VERSION 5.7 ;
  NOWIREEXTENSIONATPIN ON ;
  DIVIDERCHAR "/" ;
  BUSBITCHARS "[]" ;
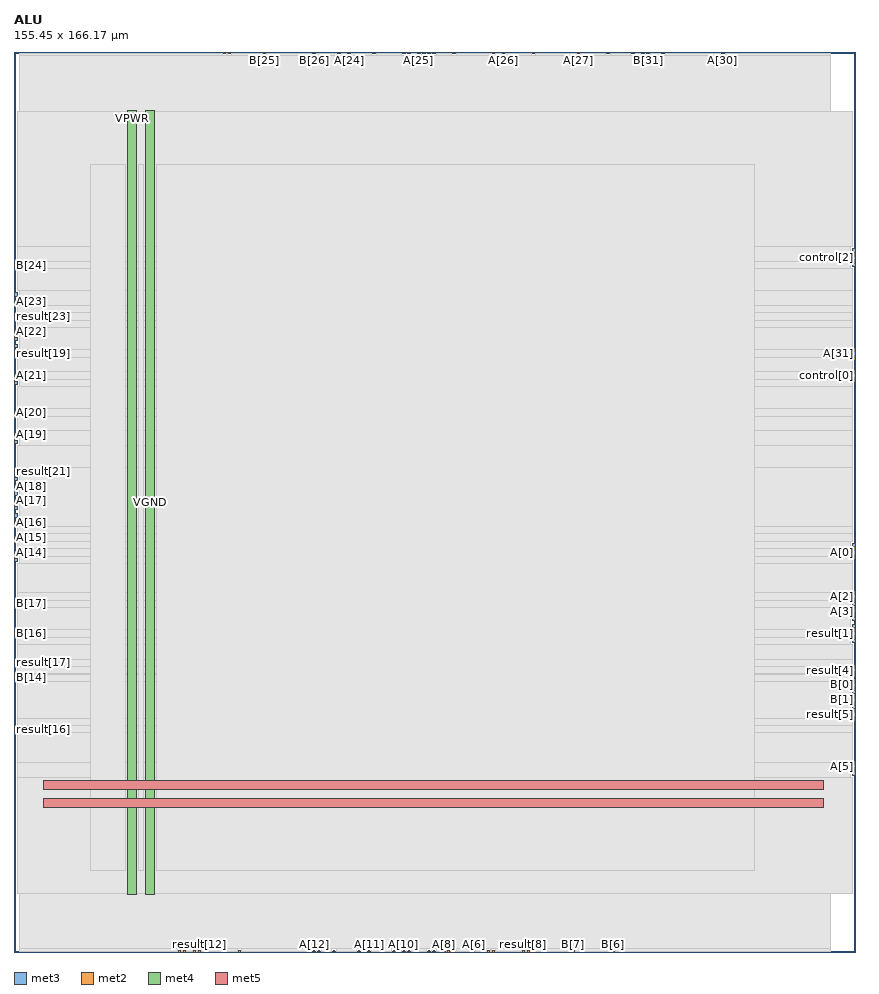
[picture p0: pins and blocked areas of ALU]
MACRO ALU
  CLASS BLOCK ;
  FOREIGN ALU ;
  ORIGIN 0.000 0.000 ;
  SIZE 155.450 BY 166.170 ;
  PIN A[0]
    DIRECTION INPUT ;
    USE SIGNAL ;
    ANTENNAGATEAREA 0.126000 ;
    PORT
      LAYER met3 ;
        RECT 154.850 73.480 155.450 74.080 ;
    END
  END A[0]
  PIN A[10]
    DIRECTION INPUT ;
    USE SIGNAL ;
    ANTENNAGATEAREA 0.213000 ;
    PORT
      LAYER met2 ;
        RECT 71.850 0.000 72.130 0.280 ;
    END
  END A[10]
  PIN A[11]
    DIRECTION INPUT ;
    USE SIGNAL ;
    ANTENNAGATEAREA 0.213000 ;
    PORT
      LAYER met2 ;
        RECT 65.410 0.000 65.690 0.280 ;
    END
  END A[11]
  PIN A[12]
    DIRECTION INPUT ;
    USE SIGNAL ;
    ANTENNAGATEAREA 0.126000 ;
    PORT
      LAYER met2 ;
        RECT 55.290 0.000 55.570 0.280 ;
    END
  END A[12]
  PIN A[13]
    DIRECTION INPUT ;
    USE SIGNAL ;
    ANTENNAGATEAREA 0.213000 ;
    PORT
      LAYER met2 ;
        RECT 30.450 0.000 30.730 0.280 ;
    END
  END A[13]
  PIN A[14]
    DIRECTION INPUT ;
    USE SIGNAL ;
    ANTENNAGATEAREA 0.126000 ;
    PORT
      LAYER met3 ;
        RECT 0.000 73.480 0.600 74.080 ;
    END
  END A[14]
  PIN A[15]
    DIRECTION INPUT ;
    USE SIGNAL ;
    ANTENNAGATEAREA 0.213000 ;
    PORT
      LAYER met3 ;
        RECT 0.000 76.200 0.600 76.800 ;
    END
  END A[15]
  PIN A[16]
    DIRECTION INPUT ;
    USE SIGNAL ;
    ANTENNAGATEAREA 0.213000 ;
    PORT
      LAYER met3 ;
        RECT 0.000 78.920 0.600 79.520 ;
    END
  END A[16]
  PIN A[17]
    DIRECTION INPUT ;
    USE SIGNAL ;
    ANTENNAGATEAREA 0.213000 ;
    PORT
      LAYER met3 ;
        RECT 0.000 83.000 0.600 83.600 ;
    END
  END A[17]
  PIN A[18]
    DIRECTION INPUT ;
    USE SIGNAL ;
    ANTENNAGATEAREA 0.213000 ;
    PORT
      LAYER met3 ;
        RECT 0.000 85.720 0.600 86.320 ;
    END
  END A[18]
  PIN A[19]
    DIRECTION INPUT ;
    USE SIGNAL ;
    ANTENNAGATEAREA 0.213000 ;
    PORT
      LAYER met3 ;
        RECT 0.000 95.240 0.600 95.840 ;
    END
  END A[19]
  PIN A[1]
    DIRECTION INPUT ;
    USE SIGNAL ;
    ANTENNAGATEAREA 0.196500 ;
    PORT
      LAYER met3 ;
        RECT 154.850 74.840 155.450 75.440 ;
    END
  END A[1]
  PIN A[20]
    DIRECTION INPUT ;
    USE SIGNAL ;
    ANTENNAGATEAREA 0.213000 ;
    PORT
      LAYER met3 ;
        RECT 0.000 99.320 0.600 99.920 ;
    END
  END A[20]
  PIN A[21]
    DIRECTION INPUT ;
    USE SIGNAL ;
    ANTENNAGATEAREA 0.213000 ;
    PORT
      LAYER met3 ;
        RECT 0.000 106.120 0.600 106.720 ;
    END
  END A[21]
  PIN A[22]
    DIRECTION INPUT ;
    USE SIGNAL ;
    ANTENNAGATEAREA 0.213000 ;
    PORT
      LAYER met3 ;
        RECT 0.000 114.280 0.600 114.880 ;
    END
  END A[22]
  PIN A[23]
    DIRECTION INPUT ;
    USE SIGNAL ;
    ANTENNAGATEAREA 0.213000 ;
    PORT
      LAYER met3 ;
        RECT 0.000 119.720 0.600 120.320 ;
    END
  END A[23]
  PIN A[24]
    DIRECTION INPUT ;
    USE SIGNAL ;
    ANTENNAGATEAREA 0.213000 ;
    PORT
      LAYER met2 ;
        RECT 61.730 165.890 62.010 166.170 ;
    END
  END A[24]
  PIN A[25]
    DIRECTION INPUT ;
    USE SIGNAL ;
    ANTENNAGATEAREA 0.213000 ;
    PORT
      LAYER met2 ;
        RECT 74.610 165.890 74.890 166.170 ;
    END
  END A[25]
  PIN A[26]
    DIRECTION INPUT ;
    USE SIGNAL ;
    ANTENNAGATEAREA 0.213000 ;
    PORT
      LAYER met2 ;
        RECT 90.250 165.890 90.530 166.170 ;
    END
  END A[26]
  PIN A[27]
    DIRECTION INPUT ;
    USE SIGNAL ;
    ANTENNAGATEAREA 0.213000 ;
    PORT
      LAYER met2 ;
        RECT 104.050 165.890 104.330 166.170 ;
    END
  END A[27]
  PIN A[28]
    DIRECTION INPUT ;
    USE SIGNAL ;
    ANTENNAGATEAREA 0.213000 ;
    PORT
      LAYER met2 ;
        RECT 116.010 165.890 116.290 166.170 ;
    END
  END A[28]
  PIN A[29]
    DIRECTION INPUT ;
    USE SIGNAL ;
    ANTENNAGATEAREA 0.213000 ;
    PORT
      LAYER met2 ;
        RECT 114.170 165.890 114.450 166.170 ;
    END
  END A[29]
  PIN A[2]
    DIRECTION INPUT ;
    USE SIGNAL ;
    ANTENNAGATEAREA 0.213000 ;
    PORT
      LAYER met3 ;
        RECT 154.850 65.320 155.450 65.920 ;
    END
  END A[2]
  PIN A[30]
    DIRECTION INPUT ;
    USE SIGNAL ;
    ANTENNAGATEAREA 0.213000 ;
    PORT
      LAYER met2 ;
        RECT 130.730 165.890 131.010 166.170 ;
    END
  END A[30]
  PIN A[31]
    DIRECTION INPUT ;
    USE SIGNAL ;
    ANTENNAGATEAREA 0.213000 ;
    PORT
      LAYER met3 ;
        RECT 154.850 110.200 155.450 110.800 ;
    END
  END A[31]
  PIN A[3]
    DIRECTION INPUT ;
    USE SIGNAL ;
    ANTENNAGATEAREA 0.196500 ;
    PORT
      LAYER met3 ;
        RECT 154.850 62.600 155.450 63.200 ;
    END
  END A[3]
  PIN A[4]
    DIRECTION INPUT ;
    USE SIGNAL ;
    ANTENNAGATEAREA 0.495000 ;
    PORT
      LAYER met3 ;
        RECT 154.850 44.920 155.450 45.520 ;
    END
  END A[4]
  PIN A[5]
    DIRECTION INPUT ;
    USE SIGNAL ;
    ANTENNAGATEAREA 0.213000 ;
    PORT
      LAYER met3 ;
        RECT 154.850 34.040 155.450 34.640 ;
    END
  END A[5]
  PIN A[6]
    DIRECTION INPUT ;
    USE SIGNAL ;
    ANTENNAGATEAREA 0.126000 ;
    PORT
      LAYER met2 ;
        RECT 84.730 0.000 85.010 0.280 ;
    END
  END A[6]
  PIN A[7]
    DIRECTION INPUT ;
    USE SIGNAL ;
    ANTENNAGATEAREA 0.213000 ;
    PORT
      LAYER met2 ;
        RECT 81.050 0.000 81.330 0.280 ;
    END
  END A[7]
  PIN A[8]
    DIRECTION INPUT ;
    USE SIGNAL ;
    ANTENNAGATEAREA 0.126000 ;
    PORT
      LAYER met2 ;
        RECT 79.210 0.000 79.490 0.280 ;
    END
  END A[8]
  PIN A[9]
    DIRECTION INPUT ;
    USE SIGNAL ;
    ANTENNAGATEAREA 0.213000 ;
    PORT
      LAYER met2 ;
        RECT 77.370 0.000 77.650 0.280 ;
    END
  END A[9]
  PIN B[0]
    DIRECTION INPUT ;
    USE SIGNAL ;
    ANTENNAGATEAREA 0.742500 ;
    PORT
      LAYER met3 ;
        RECT 154.850 49.000 155.450 49.600 ;
    END
  END B[0]
  PIN B[10]
    DIRECTION INPUT ;
    USE SIGNAL ;
    ANTENNAGATEAREA 0.213000 ;
    PORT
      LAYER met2 ;
        RECT 76.450 0.000 76.730 0.280 ;
    END
  END B[10]
  PIN B[11]
    DIRECTION INPUT ;
    USE SIGNAL ;
    ANTENNAGATEAREA 0.213000 ;
    PORT
      LAYER met2 ;
        RECT 70.010 0.000 70.290 0.280 ;
    END
  END B[11]
  PIN B[12]
    DIRECTION INPUT ;
    USE SIGNAL ;
    ANTENNAGATEAREA 0.213000 ;
    PORT
      LAYER met2 ;
        RECT 56.210 0.000 56.490 0.280 ;
    END
  END B[12]
  PIN B[13]
    DIRECTION INPUT ;
    USE SIGNAL ;
    ANTENNAGATEAREA 0.126000 ;
    PORT
      LAYER met2 ;
        RECT 31.370 0.000 31.650 0.280 ;
    END
  END B[13]
  PIN B[14]
    DIRECTION INPUT ;
    USE SIGNAL ;
    ANTENNAGATEAREA 0.213000 ;
    PORT
      LAYER met3 ;
        RECT 0.000 50.360 0.600 50.960 ;
    END
  END B[14]
  PIN B[15]
    DIRECTION INPUT ;
    USE SIGNAL ;
    ANTENNAGATEAREA 0.213000 ;
    PORT
      LAYER met2 ;
        RECT 41.490 0.000 41.770 0.280 ;
    END
  END B[15]
  PIN B[16]
    DIRECTION INPUT ;
    USE SIGNAL ;
    ANTENNAGATEAREA 0.213000 ;
    PORT
      LAYER met3 ;
        RECT 0.000 58.520 0.600 59.120 ;
    END
  END B[16]
  PIN B[17]
    DIRECTION INPUT ;
    USE SIGNAL ;
    ANTENNAGATEAREA 0.213000 ;
    PORT
      LAYER met3 ;
        RECT 0.000 63.960 0.600 64.560 ;
    END
  END B[17]
  PIN B[18]
    DIRECTION INPUT ;
    USE SIGNAL ;
    ANTENNAGATEAREA 0.213000 ;
    PORT
      LAYER met3 ;
        RECT 0.000 72.120 0.600 72.720 ;
    END
  END B[18]
  PIN B[19]
    DIRECTION INPUT ;
    USE SIGNAL ;
    ANTENNAGATEAREA 0.213000 ;
    PORT
      LAYER met3 ;
        RECT 0.000 80.280 0.600 80.880 ;
    END
  END B[19]
  PIN B[1]
    DIRECTION INPUT ;
    USE SIGNAL ;
    ANTENNAGATEAREA 0.742500 ;
    PORT
      LAYER met3 ;
        RECT 154.850 46.280 155.450 46.880 ;
    END
  END B[1]
  PIN B[20]
    DIRECTION INPUT ;
    USE SIGNAL ;
    ANTENNAGATEAREA 0.213000 ;
    PORT
      LAYER met3 ;
        RECT 0.000 93.880 0.600 94.480 ;
    END
  END B[20]
  PIN B[21]
    DIRECTION INPUT ;
    USE SIGNAL ;
    ANTENNAGATEAREA 0.213000 ;
    PORT
      LAYER met3 ;
        RECT 0.000 104.760 0.600 105.360 ;
    END
  END B[21]
  PIN B[22]
    DIRECTION INPUT ;
    USE SIGNAL ;
    ANTENNAGATEAREA 0.213000 ;
    PORT
      LAYER met3 ;
        RECT 0.000 112.920 0.600 113.520 ;
    END
  END B[22]
  PIN B[23]
    DIRECTION INPUT ;
    USE SIGNAL ;
    ANTENNAGATEAREA 0.213000 ;
    PORT
      LAYER met3 ;
        RECT 0.000 121.080 0.600 121.680 ;
    END
  END B[23]
  PIN B[24]
    DIRECTION INPUT ;
    USE SIGNAL ;
    ANTENNAGATEAREA 0.213000 ;
    PORT
      LAYER met3 ;
        RECT 0.000 126.520 0.600 127.120 ;
    END
  END B[24]
  PIN B[25]
    DIRECTION INPUT ;
    USE SIGNAL ;
    ANTENNAGATEAREA 0.213000 ;
    PORT
      LAYER met2 ;
        RECT 46.090 165.890 46.370 166.170 ;
    END
  END B[25]
  PIN B[26]
    DIRECTION INPUT ;
    USE SIGNAL ;
    ANTENNAGATEAREA 0.213000 ;
    PORT
      LAYER met2 ;
        RECT 55.290 165.890 55.570 166.170 ;
    END
  END B[26]
  PIN B[27]
    DIRECTION INPUT ;
    USE SIGNAL ;
    ANTENNAGATEAREA 0.213000 ;
    PORT
      LAYER met2 ;
        RECT 59.890 165.890 60.170 166.170 ;
    END
  END B[27]
  PIN B[28]
    DIRECTION INPUT ;
    USE SIGNAL ;
    ANTENNAGATEAREA 0.213000 ;
    PORT
      LAYER met2 ;
        RECT 88.410 165.890 88.690 166.170 ;
    END
  END B[28]
  PIN B[29]
    DIRECTION INPUT ;
    USE SIGNAL ;
    ANTENNAGATEAREA 0.213000 ;
    PORT
      LAYER met2 ;
        RECT 95.770 165.890 96.050 166.170 ;
    END
  END B[29]
  PIN B[2]
    DIRECTION INPUT ;
    USE SIGNAL ;
    ANTENNAGATEAREA 0.213000 ;
    PORT
      LAYER met3 ;
        RECT 154.850 61.240 155.450 61.840 ;
    END
  END B[2]
  PIN B[30]
    DIRECTION INPUT ;
    USE SIGNAL ;
    ANTENNAGATEAREA 0.213000 ;
    PORT
      LAYER met2 ;
        RECT 109.570 165.890 109.850 166.170 ;
    END
  END B[30]
  PIN B[31]
    DIRECTION INPUT ;
    USE SIGNAL ;
    ANTENNAGATEAREA 0.213000 ;
    PORT
      LAYER met2 ;
        RECT 116.930 165.890 117.210 166.170 ;
    END
  END B[31]
  PIN B[3]
    DIRECTION INPUT ;
    USE SIGNAL ;
    ANTENNAGATEAREA 0.213000 ;
    PORT
      LAYER met3 ;
        RECT 154.850 63.960 155.450 64.560 ;
    END
  END B[3]
  PIN B[4]
    DIRECTION INPUT ;
    USE SIGNAL ;
    ANTENNAGATEAREA 0.742500 ;
    PORT
      LAYER met3 ;
        RECT 154.850 47.640 155.450 48.240 ;
    END
  END B[4]
  PIN B[5]
    DIRECTION INPUT ;
    USE SIGNAL ;
    ANTENNAGATEAREA 0.126000 ;
    PORT
      LAYER met3 ;
        RECT 154.850 32.680 155.450 33.280 ;
    END
  END B[5]
  PIN B[6]
    DIRECTION INPUT ;
    USE SIGNAL ;
    ANTENNAGATEAREA 0.126000 ;
    PORT
      LAYER met2 ;
        RECT 110.490 0.000 110.770 0.280 ;
    END
  END B[6]
  PIN B[7]
    DIRECTION INPUT ;
    USE SIGNAL ;
    ANTENNAGATEAREA 0.213000 ;
    PORT
      LAYER met2 ;
        RECT 103.130 0.000 103.410 0.280 ;
    END
  END B[7]
  PIN B[8]
    DIRECTION INPUT ;
    USE SIGNAL ;
    ANTENNAGATEAREA 0.213000 ;
    PORT
      LAYER met2 ;
        RECT 87.490 0.000 87.770 0.280 ;
    END
  END B[8]
  PIN B[9]
    DIRECTION INPUT ;
    USE SIGNAL ;
    ANTENNAGATEAREA 0.213000 ;
    PORT
      LAYER met2 ;
        RECT 80.130 0.000 80.410 0.280 ;
    END
  END B[9]
  PIN VGND
    DIRECTION INOUT ;
    USE GROUND ;
    PORT
      LAYER met4 ;
        RECT 24.340 10.640 25.940 155.280 ;
    END
    PORT
      LAYER met5 ;
        RECT 5.520 30.030 149.500 31.630 ;
    END
  END VGND
  PIN VPWR
    DIRECTION INOUT ;
    USE POWER ;
    PORT
      LAYER met4 ;
        RECT 21.040 10.640 22.640 155.280 ;
    END
    PORT
      LAYER met5 ;
        RECT 5.520 26.730 149.500 28.330 ;
    END
  END VPWR
  PIN control[0]
    DIRECTION INPUT ;
    USE SIGNAL ;
    ANTENNAGATEAREA 0.213000 ;
    PORT
      LAYER met3 ;
        RECT 154.850 106.120 155.450 106.720 ;
    END
  END control[0]
  PIN control[1]
    DIRECTION INPUT ;
    USE SIGNAL ;
    ANTENNAGATEAREA 0.213000 ;
    PORT
      LAYER met3 ;
        RECT 154.850 126.520 155.450 127.120 ;
    END
  END control[1]
  PIN control[2]
    DIRECTION INPUT ;
    USE SIGNAL ;
    ANTENNAGATEAREA 0.213000 ;
    PORT
      LAYER met3 ;
        RECT 154.850 127.880 155.450 128.480 ;
    END
  END control[2]
  PIN control[3]
    DIRECTION INPUT ;
    USE SIGNAL ;
    ANTENNAGATEAREA 0.213000 ;
    PORT
      LAYER met3 ;
        RECT 154.850 129.240 155.450 129.840 ;
    END
  END control[3]
  PIN result[0]
    DIRECTION OUTPUT ;
    USE SIGNAL ;
    ANTENNADIFFAREA 1.336500 ;
    PORT
      LAYER met2 ;
        RECT 119.690 165.890 119.970 166.170 ;
    END
  END result[0]
  PIN result[10]
    DIRECTION OUTPUT ;
    USE SIGNAL ;
    ANTENNADIFFAREA 1.782000 ;
    PORT
      LAYER met2 ;
        RECT 72.770 0.000 73.050 0.280 ;
    END
  END result[10]
  PIN result[11]
    DIRECTION OUTPUT ;
    USE SIGNAL ;
    ANTENNADIFFAREA 1.782000 ;
    PORT
      LAYER met2 ;
        RECT 63.570 0.000 63.850 0.280 ;
    END
  END result[11]
  PIN result[12]
    DIRECTION OUTPUT ;
    USE SIGNAL ;
    ANTENNADIFFAREA 1.336500 ;
    PORT
      LAYER met2 ;
        RECT 34.130 0.000 34.410 0.280 ;
    END
  END result[12]
  PIN result[13]
    DIRECTION OUTPUT ;
    USE SIGNAL ;
    ANTENNADIFFAREA 1.336500 ;
    PORT
      LAYER met2 ;
        RECT 33.210 0.000 33.490 0.280 ;
    END
  END result[13]
  PIN result[14]
    DIRECTION OUTPUT ;
    USE SIGNAL ;
    ANTENNADIFFAREA 0.383400 ;
    PORT
      LAYER met2 ;
        RECT 58.970 0.000 59.250 0.280 ;
    END
  END result[14]
  PIN result[15]
    DIRECTION OUTPUT ;
    USE SIGNAL ;
    ANTENNADIFFAREA 0.891000 ;
    PORT
      LAYER met3 ;
        RECT 0.000 81.640 0.600 82.240 ;
    END
  END result[15]
  PIN result[16]
    DIRECTION OUTPUT ;
    USE SIGNAL ;
    ANTENNADIFFAREA 1.782000 ;
    PORT
      LAYER met3 ;
        RECT 0.000 40.840 0.600 41.440 ;
    END
  END result[16]
  PIN result[17]
    DIRECTION OUTPUT ;
    USE SIGNAL ;
    ANTENNADIFFAREA 1.336500 ;
    PORT
      LAYER met3 ;
        RECT 0.000 53.080 0.600 53.680 ;
    END
  END result[17]
  PIN result[18]
    DIRECTION OUTPUT ;
    USE SIGNAL ;
    ANTENNADIFFAREA 1.782000 ;
    PORT
      LAYER met3 ;
        RECT 0.000 84.360 0.600 84.960 ;
    END
  END result[18]
  PIN result[19]
    DIRECTION OUTPUT ;
    USE SIGNAL ;
    ANTENNADIFFAREA 1.782000 ;
    PORT
      LAYER met3 ;
        RECT 0.000 110.200 0.600 110.800 ;
    END
  END result[19]
  PIN result[1]
    DIRECTION OUTPUT ;
    USE SIGNAL ;
    ANTENNADIFFAREA 0.702900 ;
    PORT
      LAYER met3 ;
        RECT 154.850 58.520 155.450 59.120 ;
    END
  END result[1]
  PIN result[20]
    DIRECTION OUTPUT ;
    USE SIGNAL ;
    ANTENNADIFFAREA 1.782000 ;
    PORT
      LAYER met3 ;
        RECT 0.000 87.080 0.600 87.680 ;
    END
  END result[20]
  PIN result[21]
    DIRECTION OUTPUT ;
    USE SIGNAL ;
    ANTENNADIFFAREA 1.336500 ;
    PORT
      LAYER met3 ;
        RECT 0.000 88.440 0.600 89.040 ;
    END
  END result[21]
  PIN result[22]
    DIRECTION OUTPUT ;
    USE SIGNAL ;
    ANTENNADIFFAREA 1.336500 ;
    PORT
      LAYER met3 ;
        RECT 0.000 111.560 0.600 112.160 ;
    END
  END result[22]
  PIN result[23]
    DIRECTION OUTPUT ;
    USE SIGNAL ;
    ANTENNADIFFAREA 1.336500 ;
    PORT
      LAYER met3 ;
        RECT 0.000 117.000 0.600 117.600 ;
    END
  END result[23]
  PIN result[24]
    DIRECTION OUTPUT ;
    USE SIGNAL ;
    ANTENNADIFFAREA 1.336500 ;
    PORT
      LAYER met2 ;
        RECT 38.730 165.890 39.010 166.170 ;
    END
  END result[24]
  PIN result[25]
    DIRECTION OUTPUT ;
    USE SIGNAL ;
    ANTENNADIFFAREA 1.782000 ;
    PORT
      LAYER met2 ;
        RECT 39.650 165.890 39.930 166.170 ;
    END
  END result[25]
  PIN result[26]
    DIRECTION OUTPUT ;
    USE SIGNAL ;
    ANTENNADIFFAREA 1.782000 ;
    PORT
      LAYER met2 ;
        RECT 66.330 165.890 66.610 166.170 ;
    END
  END result[26]
  PIN result[27]
    DIRECTION OUTPUT ;
    USE SIGNAL ;
    ANTENNADIFFAREA 1.782000 ;
    PORT
      LAYER met2 ;
        RECT 71.850 165.890 72.130 166.170 ;
    END
  END result[27]
  PIN result[28]
    DIRECTION OUTPUT ;
    USE SIGNAL ;
    ANTENNADIFFAREA 1.782000 ;
    PORT
      LAYER met2 ;
        RECT 72.770 165.890 73.050 166.170 ;
    END
  END result[28]
  PIN result[29]
    DIRECTION OUTPUT ;
    USE SIGNAL ;
    ANTENNADIFFAREA 1.336500 ;
    PORT
      LAYER met2 ;
        RECT 77.370 165.890 77.650 166.170 ;
    END
  END result[29]
  PIN result[2]
    DIRECTION OUTPUT ;
    USE SIGNAL ;
    ANTENNADIFFAREA 0.702900 ;
    PORT
      LAYER met3 ;
        RECT 154.850 59.880 155.450 60.480 ;
    END
  END result[2]
  PIN result[30]
    DIRECTION OUTPUT ;
    USE SIGNAL ;
    ANTENNADIFFAREA 1.336500 ;
    PORT
      LAYER met2 ;
        RECT 81.050 165.890 81.330 166.170 ;
    END
  END result[30]
  PIN result[31]
    DIRECTION OUTPUT ;
    USE SIGNAL ;
    ANTENNADIFFAREA 1.782000 ;
    PORT
      LAYER met2 ;
        RECT 75.530 165.890 75.810 166.170 ;
    END
  END result[31]
  PIN result[3]
    DIRECTION OUTPUT ;
    USE SIGNAL ;
    ANTENNAGATEAREA 0.126000 ;
    ANTENNADIFFAREA 0.429000 ;
    PORT
      LAYER met3 ;
        RECT 154.850 57.160 155.450 57.760 ;
    END
  END result[3]
  PIN result[4]
    DIRECTION OUTPUT ;
    USE SIGNAL ;
    ANTENNADIFFAREA 0.383400 ;
    PORT
      LAYER met3 ;
        RECT 154.850 51.720 155.450 52.320 ;
    END
  END result[4]
  PIN result[5]
    DIRECTION OUTPUT ;
    USE SIGNAL ;
    ANTENNADIFFAREA 1.336500 ;
    PORT
      LAYER met3 ;
        RECT 154.850 43.560 155.450 44.160 ;
    END
  END result[5]
  PIN result[6]
    DIRECTION OUTPUT ;
    USE SIGNAL ;
    ANTENNADIFFAREA 1.782000 ;
    PORT
      LAYER met2 ;
        RECT 94.850 0.000 95.130 0.280 ;
    END
  END result[6]
  PIN result[7]
    DIRECTION OUTPUT ;
    USE SIGNAL ;
    ANTENNADIFFAREA 1.336500 ;
    PORT
      LAYER met2 ;
        RECT 95.770 0.000 96.050 0.280 ;
    END
  END result[7]
  PIN result[8]
    DIRECTION OUTPUT ;
    USE SIGNAL ;
    ANTENNADIFFAREA 1.782000 ;
    PORT
      LAYER met2 ;
        RECT 93.930 0.000 94.210 0.280 ;
    END
  END result[8]
  PIN result[9]
    DIRECTION OUTPUT ;
    USE SIGNAL ;
    ANTENNADIFFAREA 1.336500 ;
    PORT
      LAYER met2 ;
        RECT 88.410 0.000 88.690 0.280 ;
    END
  END result[9]
  PIN zero
    DIRECTION OUTPUT ;
    USE SIGNAL ;
    ANTENNADIFFAREA 1.336500 ;
    PORT
      LAYER met2 ;
        RECT 76.450 165.890 76.730 166.170 ;
    END
  END zero
  OBS
      LAYER nwell ;
        RECT 5.330 10.795 149.690 155.230 ;
      LAYER li1 ;
        RECT 5.520 10.795 149.500 155.125 ;
      LAYER met1 ;
        RECT 0.990 10.640 150.810 155.280 ;
      LAYER met2 ;
        RECT 1.010 165.610 38.450 165.890 ;
        RECT 39.290 165.610 39.370 165.890 ;
        RECT 40.210 165.610 45.810 165.890 ;
        RECT 46.650 165.610 55.010 165.890 ;
        RECT 55.850 165.610 59.610 165.890 ;
        RECT 60.450 165.610 61.450 165.890 ;
        RECT 62.290 165.610 66.050 165.890 ;
        RECT 66.890 165.610 71.570 165.890 ;
        RECT 72.410 165.610 72.490 165.890 ;
        RECT 73.330 165.610 74.330 165.890 ;
        RECT 75.170 165.610 75.250 165.890 ;
        RECT 76.090 165.610 76.170 165.890 ;
        RECT 77.010 165.610 77.090 165.890 ;
        RECT 77.930 165.610 80.770 165.890 ;
        RECT 81.610 165.610 88.130 165.890 ;
        RECT 88.970 165.610 89.970 165.890 ;
        RECT 90.810 165.610 95.490 165.890 ;
        RECT 96.330 165.610 103.770 165.890 ;
        RECT 104.610 165.610 109.290 165.890 ;
        RECT 110.130 165.610 113.890 165.890 ;
        RECT 114.730 165.610 115.730 165.890 ;
        RECT 116.570 165.610 116.650 165.890 ;
        RECT 117.490 165.610 119.410 165.890 ;
        RECT 120.250 165.610 130.450 165.890 ;
        RECT 131.290 165.610 150.790 165.890 ;
        RECT 1.010 0.560 150.790 165.610 ;
        RECT 1.010 0.070 30.170 0.560 ;
        RECT 31.010 0.070 31.090 0.560 ;
        RECT 31.930 0.070 32.930 0.560 ;
        RECT 33.770 0.070 33.850 0.560 ;
        RECT 34.690 0.070 41.210 0.560 ;
        RECT 42.050 0.070 55.010 0.560 ;
        RECT 55.850 0.070 55.930 0.560 ;
        RECT 56.770 0.070 58.690 0.560 ;
        RECT 59.530 0.070 63.290 0.560 ;
        RECT 64.130 0.070 65.130 0.560 ;
        RECT 65.970 0.070 69.730 0.560 ;
        RECT 70.570 0.070 71.570 0.560 ;
        RECT 72.410 0.070 72.490 0.560 ;
        RECT 73.330 0.070 76.170 0.560 ;
        RECT 77.010 0.070 77.090 0.560 ;
        RECT 77.930 0.070 78.930 0.560 ;
        RECT 79.770 0.070 79.850 0.560 ;
        RECT 80.690 0.070 80.770 0.560 ;
        RECT 81.610 0.070 84.450 0.560 ;
        RECT 85.290 0.070 87.210 0.560 ;
        RECT 88.050 0.070 88.130 0.560 ;
        RECT 88.970 0.070 93.650 0.560 ;
        RECT 94.490 0.070 94.570 0.560 ;
        RECT 95.410 0.070 95.490 0.560 ;
        RECT 96.330 0.070 102.850 0.560 ;
        RECT 103.690 0.070 110.210 0.560 ;
        RECT 111.050 0.070 150.790 0.560 ;
      LAYER met3 ;
        RECT 0.600 130.240 154.850 155.205 ;
        RECT 0.600 127.520 154.450 130.240 ;
        RECT 1.000 126.120 154.450 127.520 ;
        RECT 0.600 122.080 154.850 126.120 ;
        RECT 1.000 119.320 154.850 122.080 ;
        RECT 0.600 118.000 154.850 119.320 ;
        RECT 1.000 116.600 154.850 118.000 ;
        RECT 0.600 115.280 154.850 116.600 ;
        RECT 1.000 111.200 154.850 115.280 ;
        RECT 1.000 109.800 154.450 111.200 ;
        RECT 0.600 107.120 154.850 109.800 ;
        RECT 1.000 105.720 154.450 107.120 ;
        RECT 1.000 104.360 154.850 105.720 ;
        RECT 0.600 100.320 154.850 104.360 ;
        RECT 1.000 98.920 154.850 100.320 ;
        RECT 0.600 96.240 154.850 98.920 ;
        RECT 1.000 93.480 154.850 96.240 ;
        RECT 0.600 89.440 154.850 93.480 ;
        RECT 1.000 78.520 154.850 89.440 ;
        RECT 0.600 77.200 154.850 78.520 ;
        RECT 1.000 75.840 154.850 77.200 ;
        RECT 1.000 75.800 154.450 75.840 ;
        RECT 0.600 74.480 154.450 75.800 ;
        RECT 1.000 73.080 154.450 74.480 ;
        RECT 1.000 71.720 154.850 73.080 ;
        RECT 0.600 66.320 154.850 71.720 ;
        RECT 0.600 64.960 154.450 66.320 ;
        RECT 1.000 63.560 154.450 64.960 ;
        RECT 0.600 59.520 154.450 63.560 ;
        RECT 1.000 58.120 154.450 59.520 ;
        RECT 0.600 56.760 154.450 58.120 ;
        RECT 0.600 54.080 154.850 56.760 ;
        RECT 1.000 52.720 154.850 54.080 ;
        RECT 1.000 52.680 154.450 52.720 ;
        RECT 0.600 51.360 154.450 52.680 ;
        RECT 1.000 51.320 154.450 51.360 ;
        RECT 1.000 50.000 154.850 51.320 ;
        RECT 1.000 49.960 154.450 50.000 ;
        RECT 0.600 43.160 154.450 49.960 ;
        RECT 0.600 41.840 154.850 43.160 ;
        RECT 1.000 40.440 154.850 41.840 ;
        RECT 0.600 35.040 154.850 40.440 ;
        RECT 0.600 32.280 154.450 35.040 ;
        RECT 0.600 10.715 154.850 32.280 ;
      LAYER met4 ;
        RECT 14.095 15.135 20.640 145.345 ;
        RECT 23.040 15.135 23.940 145.345 ;
        RECT 26.340 15.135 136.785 145.345 ;
  END
END ALU
END LIBRARY

